VERSION 5.7 ;
  NOWIREEXTENSIONATPIN ON ;
  DIVIDERCHAR "/" ;
  BUSBITCHARS "[]" ;
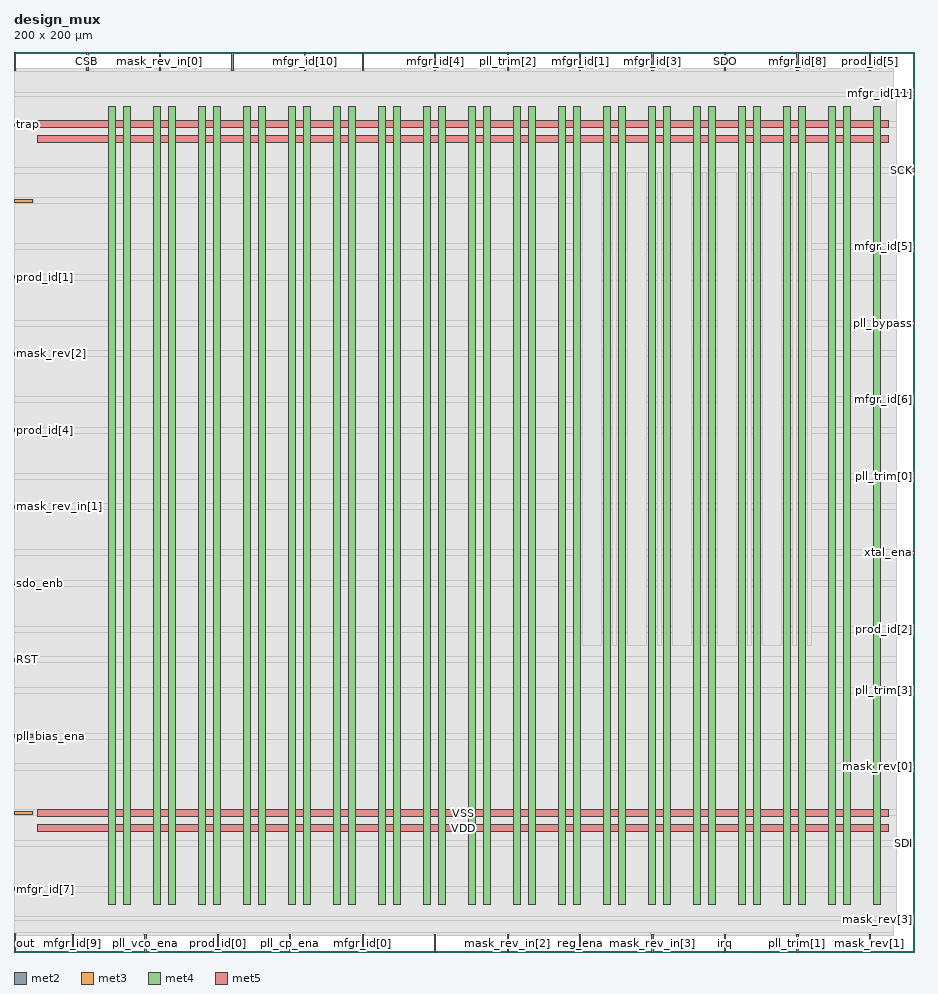
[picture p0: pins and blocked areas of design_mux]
MACRO design_mux
  CLASS BLOCK ;
  FOREIGN design_mux ;
  ORIGIN 0.000 0.000 ;
  SIZE 200.000 BY 200.000 ;
  PIN CSB
    DIRECTION INPUT ;
    USE SIGNAL ;
    ANTENNAGATEAREA 0.196500 ;
    PORT
      LAYER met2 ;
        RECT 16.190 196.000 16.470 200.000 ;
    END
  END CSB
  PIN RST
    DIRECTION INPUT ;
    USE SIGNAL ;
    ANTENNAGATEAREA 0.691500 ;
    PORT
      LAYER met3 ;
        RECT 0.000 64.640 4.000 65.240 ;
    END
  END RST
  PIN SCK
    DIRECTION INPUT ;
    USE SIGNAL ;
    ANTENNAGATEAREA 0.852000 ;
    PORT
      LAYER met3 ;
        RECT 196.000 173.440 200.000 174.040 ;
    END
  END SCK
  PIN SDI
    DIRECTION INPUT ;
    USE SIGNAL ;
    ANTENNAGATEAREA 1.557000 ;
    PORT
      LAYER met3 ;
        RECT 196.000 23.840 200.000 24.440 ;
    END
  END SDI
  PIN SDO
    DIRECTION OUTPUT TRISTATE ;
    USE SIGNAL ;
    ANTENNAGATEAREA 0.247500 ;
    ANTENNADIFFAREA 0.445500 ;
    PORT
      LAYER met2 ;
        RECT 157.870 196.000 158.150 200.000 ;
    END
  END SDO
  PIN VDD
    DIRECTION INOUT ;
    USE SIGNAL ;
    PORT
      LAYER met3 ;
        RECT 0.000 30.640 4.000 31.240 ;
    END
    PORT
      LAYER met4 ;
        RECT 21.040 10.640 22.640 187.920 ;
    END
    PORT
      LAYER met4 ;
        RECT 31.040 10.640 32.640 187.920 ;
    END
    PORT
      LAYER met4 ;
        RECT 41.040 10.640 42.640 187.920 ;
    END
    PORT
      LAYER met4 ;
        RECT 51.040 10.640 52.640 187.920 ;
    END
    PORT
      LAYER met4 ;
        RECT 61.040 10.640 62.640 187.920 ;
    END
    PORT
      LAYER met4 ;
        RECT 71.040 10.640 72.640 187.920 ;
    END
    PORT
      LAYER met4 ;
        RECT 81.040 10.640 82.640 187.920 ;
    END
    PORT
      LAYER met4 ;
        RECT 91.040 10.640 92.640 187.920 ;
    END
    PORT
      LAYER met4 ;
        RECT 101.040 10.640 102.640 187.920 ;
    END
    PORT
      LAYER met4 ;
        RECT 111.040 10.640 112.640 187.920 ;
    END
    PORT
      LAYER met4 ;
        RECT 121.040 10.640 122.640 187.920 ;
    END
    PORT
      LAYER met4 ;
        RECT 131.040 10.640 132.640 187.920 ;
    END
    PORT
      LAYER met4 ;
        RECT 141.040 10.640 142.640 187.920 ;
    END
    PORT
      LAYER met4 ;
        RECT 151.040 10.640 152.640 187.920 ;
    END
    PORT
      LAYER met4 ;
        RECT 161.040 10.640 162.640 187.920 ;
    END
    PORT
      LAYER met4 ;
        RECT 171.040 10.640 172.640 187.920 ;
    END
    PORT
      LAYER met4 ;
        RECT 181.040 10.640 182.640 187.920 ;
    END
    PORT
      LAYER met4 ;
        RECT 191.040 10.640 192.640 187.920 ;
    END
    PORT
      LAYER met5 ;
        RECT 5.280 26.730 194.360 28.330 ;
    END
    PORT
      LAYER met5 ;
        RECT 5.280 179.910 194.360 181.510 ;
    END
  END VDD
  PIN VSS
    DIRECTION INOUT ;
    USE SIGNAL ;
    PORT
      LAYER met3 ;
        RECT 0.000 166.640 4.000 167.240 ;
    END
    PORT
      LAYER met4 ;
        RECT 24.340 10.640 25.940 187.920 ;
    END
    PORT
      LAYER met4 ;
        RECT 34.340 10.640 35.940 187.920 ;
    END
    PORT
      LAYER met4 ;
        RECT 44.340 10.640 45.940 187.920 ;
    END
    PORT
      LAYER met4 ;
        RECT 54.340 10.640 55.940 187.920 ;
    END
    PORT
      LAYER met4 ;
        RECT 64.340 10.640 65.940 187.920 ;
    END
    PORT
      LAYER met4 ;
        RECT 74.340 10.640 75.940 187.920 ;
    END
    PORT
      LAYER met4 ;
        RECT 84.340 10.640 85.940 187.920 ;
    END
    PORT
      LAYER met4 ;
        RECT 94.340 10.640 95.940 187.920 ;
    END
    PORT
      LAYER met4 ;
        RECT 104.340 10.640 105.940 187.920 ;
    END
    PORT
      LAYER met4 ;
        RECT 114.340 10.640 115.940 187.920 ;
    END
    PORT
      LAYER met4 ;
        RECT 124.340 10.640 125.940 187.920 ;
    END
    PORT
      LAYER met4 ;
        RECT 134.340 10.640 135.940 187.920 ;
    END
    PORT
      LAYER met4 ;
        RECT 144.340 10.640 145.940 187.920 ;
    END
    PORT
      LAYER met4 ;
        RECT 154.340 10.640 155.940 187.920 ;
    END
    PORT
      LAYER met4 ;
        RECT 164.340 10.640 165.940 187.920 ;
    END
    PORT
      LAYER met4 ;
        RECT 174.340 10.640 175.940 187.920 ;
    END
    PORT
      LAYER met4 ;
        RECT 184.340 10.640 185.940 187.920 ;
    END
    PORT
      LAYER met5 ;
        RECT 5.280 30.030 194.360 31.630 ;
    END
    PORT
      LAYER met5 ;
        RECT 5.280 183.210 194.360 184.810 ;
    END
  END VSS
  PIN irq
    DIRECTION OUTPUT TRISTATE ;
    USE SIGNAL ;
    ANTENNAGATEAREA 0.654000 ;
    ANTENNADIFFAREA 0.445500 ;
    PORT
      LAYER met2 ;
        RECT 157.870 0.000 158.150 4.000 ;
    END
  END irq
  PIN mask_rev[0]
    DIRECTION OUTPUT TRISTATE ;
    USE SIGNAL ;
    ANTENNADIFFAREA 0.445500 ;
    PORT
      LAYER met3 ;
        RECT 196.000 40.840 200.000 41.440 ;
    END
  END mask_rev[0]
  PIN mask_rev[1]
    DIRECTION OUTPUT TRISTATE ;
    USE SIGNAL ;
    ANTENNADIFFAREA 0.445500 ;
    PORT
      LAYER met2 ;
        RECT 190.070 0.000 190.350 4.000 ;
    END
  END mask_rev[1]
  PIN mask_rev[2]
    DIRECTION OUTPUT TRISTATE ;
    USE SIGNAL ;
    ANTENNADIFFAREA 0.445500 ;
    PORT
      LAYER met3 ;
        RECT 0.000 132.640 4.000 133.240 ;
    END
  END mask_rev[2]
  PIN mask_rev[3]
    DIRECTION OUTPUT TRISTATE ;
    USE SIGNAL ;
    ANTENNADIFFAREA 0.445500 ;
    PORT
      LAYER met3 ;
        RECT 196.000 6.840 200.000 7.440 ;
    END
  END mask_rev[3]
  PIN mask_rev_in[0]
    DIRECTION INPUT ;
    USE SIGNAL ;
    ANTENNAGATEAREA 0.285000 ;
    PORT
      LAYER met2 ;
        RECT 32.290 196.000 32.570 200.000 ;
    END
  END mask_rev_in[0]
  PIN mask_rev_in[1]
    DIRECTION INPUT ;
    USE SIGNAL ;
    ANTENNAGATEAREA 0.406500 ;
    PORT
      LAYER met3 ;
        RECT 0.000 98.640 4.000 99.240 ;
    END
  END mask_rev_in[1]
  PIN mask_rev_in[2]
    DIRECTION INPUT ;
    USE SIGNAL ;
    ANTENNAGATEAREA 0.285000 ;
    PORT
      LAYER met2 ;
        RECT 109.570 0.000 109.850 4.000 ;
    END
  END mask_rev_in[2]
  PIN mask_rev_in[3]
    DIRECTION INPUT ;
    USE SIGNAL ;
    ANTENNAGATEAREA 0.406500 ;
    PORT
      LAYER met2 ;
        RECT 141.770 0.000 142.050 4.000 ;
    END
  END mask_rev_in[3]
  PIN mfgr_id[0]
    DIRECTION OUTPUT TRISTATE ;
    USE SIGNAL ;
    PORT
      LAYER met2 ;
        RECT 77.370 0.000 77.650 4.000 ;
    END
  END mfgr_id[0]
  PIN mfgr_id[10]
    DIRECTION OUTPUT TRISTATE ;
    USE SIGNAL ;
    PORT
      LAYER met2 ;
        RECT 64.490 196.000 64.770 200.000 ;
    END
  END mfgr_id[10]
  PIN mfgr_id[11]
    DIRECTION OUTPUT TRISTATE ;
    USE SIGNAL ;
    PORT
      LAYER met3 ;
        RECT 196.000 190.440 200.000 191.040 ;
    END
  END mfgr_id[11]
  PIN mfgr_id[1]
    DIRECTION OUTPUT TRISTATE ;
    USE SIGNAL ;
    PORT
      LAYER met2 ;
        RECT 125.670 196.000 125.950 200.000 ;
    END
  END mfgr_id[1]
  PIN mfgr_id[2]
    DIRECTION OUTPUT TRISTATE ;
    USE SIGNAL ;
    PORT
      LAYER met2 ;
        RECT 0.090 196.000 0.370 200.000 ;
    END
  END mfgr_id[2]
  PIN mfgr_id[3]
    DIRECTION OUTPUT TRISTATE ;
    USE SIGNAL ;
    PORT
      LAYER met2 ;
        RECT 141.770 196.000 142.050 200.000 ;
    END
  END mfgr_id[3]
  PIN mfgr_id[4]
    DIRECTION OUTPUT TRISTATE ;
    USE SIGNAL ;
    PORT
      LAYER met2 ;
        RECT 93.470 196.000 93.750 200.000 ;
    END
  END mfgr_id[4]
  PIN mfgr_id[5]
    DIRECTION OUTPUT TRISTATE ;
    USE SIGNAL ;
    PORT
      LAYER met3 ;
        RECT 196.000 156.440 200.000 157.040 ;
    END
  END mfgr_id[5]
  PIN mfgr_id[6]
    DIRECTION OUTPUT TRISTATE ;
    USE SIGNAL ;
    PORT
      LAYER met3 ;
        RECT 196.000 122.440 200.000 123.040 ;
    END
  END mfgr_id[6]
  PIN mfgr_id[7]
    DIRECTION OUTPUT TRISTATE ;
    USE SIGNAL ;
    PORT
      LAYER met3 ;
        RECT 0.000 13.640 4.000 14.240 ;
    END
  END mfgr_id[7]
  PIN mfgr_id[8]
    DIRECTION OUTPUT TRISTATE ;
    USE SIGNAL ;
    PORT
      LAYER met2 ;
        RECT 173.970 196.000 174.250 200.000 ;
    END
  END mfgr_id[8]
  PIN mfgr_id[9]
    DIRECTION OUTPUT TRISTATE ;
    USE SIGNAL ;
    PORT
      LAYER met2 ;
        RECT 12.970 0.000 13.250 4.000 ;
    END
  END mfgr_id[9]
  PIN out
    DIRECTION OUTPUT TRISTATE ;
    USE SIGNAL ;
    PORT
      LAYER met2 ;
        RECT 0.090 0.000 0.370 4.000 ;
    END
  END out
  PIN pll_bias_ena
    DIRECTION OUTPUT TRISTATE ;
    USE SIGNAL ;
    PORT
      LAYER met3 ;
        RECT 0.000 47.640 4.000 48.240 ;
    END
  END pll_bias_ena
  PIN pll_bypass
    DIRECTION OUTPUT TRISTATE ;
    USE SIGNAL ;
    ANTENNAGATEAREA 0.406500 ;
    ANTENNADIFFAREA 0.445500 ;
    PORT
      LAYER met3 ;
        RECT 196.000 139.440 200.000 140.040 ;
    END
  END pll_bypass
  PIN pll_cp_ena
    DIRECTION OUTPUT TRISTATE ;
    USE SIGNAL ;
    ANTENNAGATEAREA 0.406500 ;
    ANTENNADIFFAREA 0.445500 ;
    PORT
      LAYER met2 ;
        RECT 61.270 0.000 61.550 4.000 ;
    END
  END pll_cp_ena
  PIN pll_trim[0]
    DIRECTION OUTPUT TRISTATE ;
    USE SIGNAL ;
    ANTENNAGATEAREA 0.654000 ;
    ANTENNADIFFAREA 0.445500 ;
    PORT
      LAYER met3 ;
        RECT 196.000 105.440 200.000 106.040 ;
    END
  END pll_trim[0]
  PIN pll_trim[1]
    DIRECTION OUTPUT TRISTATE ;
    USE SIGNAL ;
    ANTENNAGATEAREA 0.406500 ;
    ANTENNADIFFAREA 0.445500 ;
    PORT
      LAYER met2 ;
        RECT 173.970 0.000 174.250 4.000 ;
    END
  END pll_trim[1]
  PIN pll_trim[2]
    DIRECTION OUTPUT TRISTATE ;
    USE SIGNAL ;
    ANTENNAGATEAREA 0.406500 ;
    ANTENNADIFFAREA 0.445500 ;
    PORT
      LAYER met2 ;
        RECT 109.570 196.000 109.850 200.000 ;
    END
  END pll_trim[2]
  PIN pll_trim[3]
    DIRECTION OUTPUT TRISTATE ;
    USE SIGNAL ;
    ANTENNAGATEAREA 0.285000 ;
    ANTENNADIFFAREA 0.445500 ;
    PORT
      LAYER met3 ;
        RECT 196.000 57.840 200.000 58.440 ;
    END
  END pll_trim[3]
  PIN pll_vco_ena
    DIRECTION OUTPUT TRISTATE ;
    USE SIGNAL ;
    ANTENNAGATEAREA 0.406500 ;
    ANTENNADIFFAREA 0.445500 ;
    PORT
      LAYER met2 ;
        RECT 29.070 0.000 29.350 4.000 ;
    END
  END pll_vco_ena
  PIN prod_id[0]
    DIRECTION OUTPUT TRISTATE ;
    USE SIGNAL ;
    PORT
      LAYER met2 ;
        RECT 45.170 0.000 45.450 4.000 ;
    END
  END prod_id[0]
  PIN prod_id[1]
    DIRECTION OUTPUT TRISTATE ;
    USE SIGNAL ;
    PORT
      LAYER met3 ;
        RECT 0.000 149.640 4.000 150.240 ;
    END
  END prod_id[1]
  PIN prod_id[2]
    DIRECTION OUTPUT TRISTATE ;
    USE SIGNAL ;
    PORT
      LAYER met3 ;
        RECT 196.000 71.440 200.000 72.040 ;
    END
  END prod_id[2]
  PIN prod_id[3]
    DIRECTION OUTPUT TRISTATE ;
    USE SIGNAL ;
    PORT
      LAYER met2 ;
        RECT 93.470 0.000 93.750 4.000 ;
    END
  END prod_id[3]
  PIN prod_id[4]
    DIRECTION OUTPUT TRISTATE ;
    USE SIGNAL ;
    PORT
      LAYER met3 ;
        RECT 0.000 115.640 4.000 116.240 ;
    END
  END prod_id[4]
  PIN prod_id[5]
    DIRECTION OUTPUT TRISTATE ;
    USE SIGNAL ;
    PORT
      LAYER met2 ;
        RECT 190.070 196.000 190.350 200.000 ;
    END
  END prod_id[5]
  PIN prod_id[6]
    DIRECTION OUTPUT TRISTATE ;
    USE SIGNAL ;
    PORT
      LAYER met2 ;
        RECT 48.390 196.000 48.670 200.000 ;
    END
  END prod_id[6]
  PIN prod_id[7]
    DIRECTION OUTPUT TRISTATE ;
    USE SIGNAL ;
    PORT
      LAYER met2 ;
        RECT 77.370 196.000 77.650 200.000 ;
    END
  END prod_id[7]
  PIN reg_ena
    DIRECTION OUTPUT TRISTATE ;
    USE SIGNAL ;
    ANTENNAGATEAREA 0.406500 ;
    ANTENNADIFFAREA 0.445500 ;
    PORT
      LAYER met2 ;
        RECT 125.670 0.000 125.950 4.000 ;
    END
  END reg_ena
  PIN sdo_enb
    DIRECTION OUTPUT TRISTATE ;
    USE SIGNAL ;
    ANTENNADIFFAREA 0.445500 ;
    PORT
      LAYER met3 ;
        RECT 0.000 81.640 4.000 82.240 ;
    END
  END sdo_enb
  PIN trap
    DIRECTION INPUT ;
    USE SIGNAL ;
    ANTENNAGATEAREA 0.126000 ;
    PORT
      LAYER met3 ;
        RECT 0.000 183.640 4.000 184.240 ;
    END
  END trap
  PIN xtal_ena
    DIRECTION OUTPUT TRISTATE ;
    USE SIGNAL ;
    ANTENNAGATEAREA 0.406500 ;
    ANTENNADIFFAREA 0.445500 ;
    PORT
      LAYER met3 ;
        RECT 196.000 88.440 200.000 89.040 ;
    END
  END xtal_ena
  OBS
      LAYER li1 ;
        RECT 5.520 10.795 194.120 187.765 ;
      LAYER met1 ;
        RECT 0.070 10.640 195.430 187.920 ;
      LAYER met2 ;
        RECT 0.650 195.720 15.910 196.250 ;
        RECT 16.750 195.720 32.010 196.250 ;
        RECT 32.850 195.720 48.110 196.250 ;
        RECT 48.950 195.720 64.210 196.250 ;
        RECT 65.050 195.720 77.090 196.250 ;
        RECT 77.930 195.720 93.190 196.250 ;
        RECT 94.030 195.720 109.290 196.250 ;
        RECT 110.130 195.720 125.390 196.250 ;
        RECT 126.230 195.720 141.490 196.250 ;
        RECT 142.330 195.720 157.590 196.250 ;
        RECT 158.430 195.720 173.690 196.250 ;
        RECT 174.530 195.720 189.790 196.250 ;
        RECT 190.630 195.720 195.410 196.250 ;
        RECT 0.090 4.280 195.410 195.720 ;
        RECT 0.650 3.670 12.690 4.280 ;
        RECT 13.530 3.670 28.790 4.280 ;
        RECT 29.630 3.670 44.890 4.280 ;
        RECT 45.730 3.670 60.990 4.280 ;
        RECT 61.830 3.670 77.090 4.280 ;
        RECT 77.930 3.670 93.190 4.280 ;
        RECT 94.030 3.670 109.290 4.280 ;
        RECT 110.130 3.670 125.390 4.280 ;
        RECT 126.230 3.670 141.490 4.280 ;
        RECT 142.330 3.670 157.590 4.280 ;
        RECT 158.430 3.670 173.690 4.280 ;
        RECT 174.530 3.670 189.790 4.280 ;
        RECT 190.630 3.670 195.410 4.280 ;
      LAYER met3 ;
        RECT 0.065 190.040 195.600 190.905 ;
        RECT 0.065 184.640 196.000 190.040 ;
        RECT 4.400 183.240 196.000 184.640 ;
        RECT 0.065 174.440 196.000 183.240 ;
        RECT 0.065 173.040 195.600 174.440 ;
        RECT 0.065 167.640 196.000 173.040 ;
        RECT 4.400 166.240 196.000 167.640 ;
        RECT 0.065 157.440 196.000 166.240 ;
        RECT 0.065 156.040 195.600 157.440 ;
        RECT 0.065 150.640 196.000 156.040 ;
        RECT 4.400 149.240 196.000 150.640 ;
        RECT 0.065 140.440 196.000 149.240 ;
        RECT 0.065 139.040 195.600 140.440 ;
        RECT 0.065 133.640 196.000 139.040 ;
        RECT 4.400 132.240 196.000 133.640 ;
        RECT 0.065 123.440 196.000 132.240 ;
        RECT 0.065 122.040 195.600 123.440 ;
        RECT 0.065 116.640 196.000 122.040 ;
        RECT 4.400 115.240 196.000 116.640 ;
        RECT 0.065 106.440 196.000 115.240 ;
        RECT 0.065 105.040 195.600 106.440 ;
        RECT 0.065 99.640 196.000 105.040 ;
        RECT 4.400 98.240 196.000 99.640 ;
        RECT 0.065 89.440 196.000 98.240 ;
        RECT 0.065 88.040 195.600 89.440 ;
        RECT 0.065 82.640 196.000 88.040 ;
        RECT 4.400 81.240 196.000 82.640 ;
        RECT 0.065 72.440 196.000 81.240 ;
        RECT 0.065 71.040 195.600 72.440 ;
        RECT 0.065 65.640 196.000 71.040 ;
        RECT 4.400 64.240 196.000 65.640 ;
        RECT 0.065 58.840 196.000 64.240 ;
        RECT 0.065 57.440 195.600 58.840 ;
        RECT 0.065 48.640 196.000 57.440 ;
        RECT 4.400 47.240 196.000 48.640 ;
        RECT 0.065 41.840 196.000 47.240 ;
        RECT 0.065 40.440 195.600 41.840 ;
        RECT 0.065 31.640 196.000 40.440 ;
        RECT 4.400 30.240 196.000 31.640 ;
        RECT 0.065 24.840 196.000 30.240 ;
        RECT 0.065 23.440 195.600 24.840 ;
        RECT 0.065 14.640 196.000 23.440 ;
        RECT 4.400 13.240 196.000 14.640 ;
        RECT 0.065 7.840 196.000 13.240 ;
        RECT 0.065 6.975 195.600 7.840 ;
      LAYER met4 ;
        RECT 126.340 68.175 130.640 173.225 ;
        RECT 133.040 68.175 133.940 173.225 ;
        RECT 136.340 68.175 140.640 173.225 ;
        RECT 143.040 68.175 143.940 173.225 ;
        RECT 146.340 68.175 150.640 173.225 ;
        RECT 153.040 68.175 153.940 173.225 ;
        RECT 156.340 68.175 160.640 173.225 ;
        RECT 163.040 68.175 163.940 173.225 ;
        RECT 166.340 68.175 170.640 173.225 ;
        RECT 173.040 68.175 173.940 173.225 ;
        RECT 176.340 68.175 177.265 173.225 ;
  END
END design_mux
END LIBRARY

